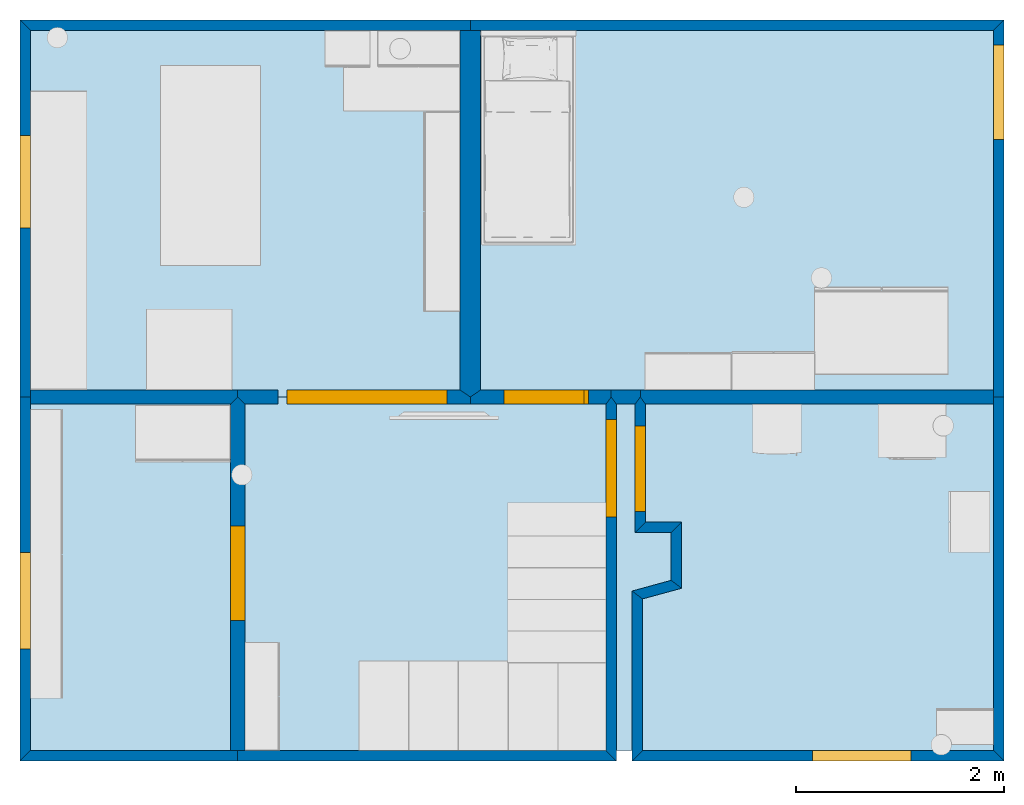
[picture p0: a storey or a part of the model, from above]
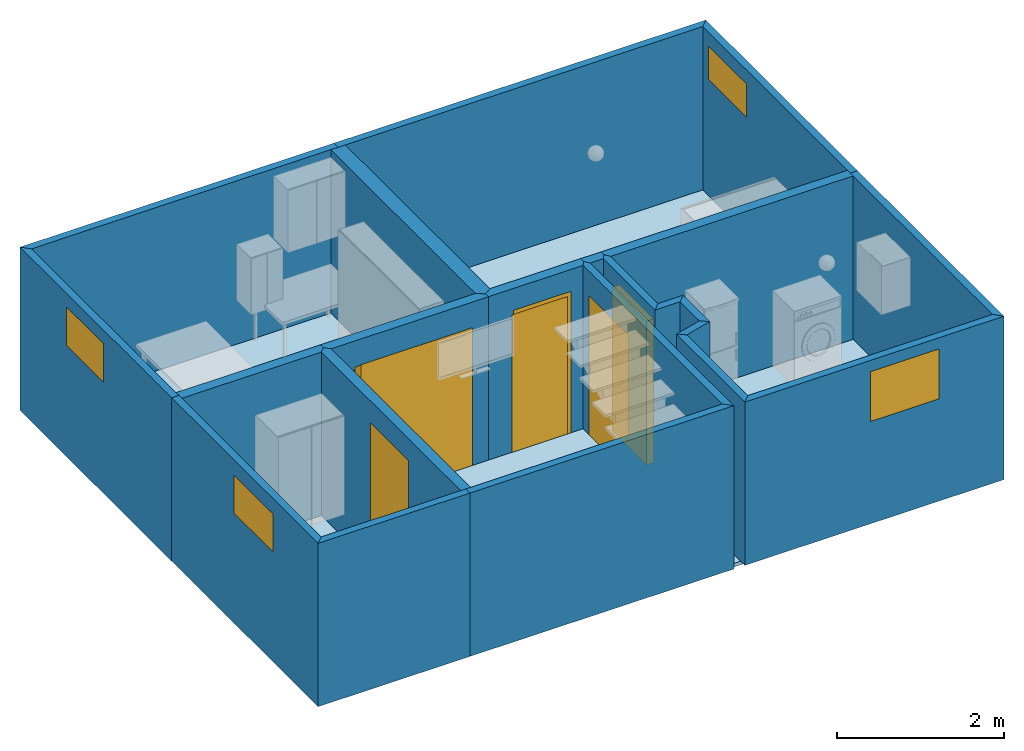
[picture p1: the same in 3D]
Properties of the parts of a building model (IFC2X3)

# File
Description: ViewDefinition [CoordinationView]
Time: 2025-05-22T09:41:32
Author: Metaroom
Written by: IfcOpenShell v0.7.0-f7c03db75
Made in: INDUSTRY_FOUNDATION_CLASSES_ARCHICAD

# IfcSite, Site
RefLatitude: 14, 49, 2; RefLongitude: 17, 34, 41
MetaroomProperties - UpVector: (np.float64(0.0), np.float64(0.0), np.float64(1.0)); IsLeftHandedCoordinateSystem: no

# IfcBuilding, Building
Pset_BuildingCommon - NumberOfStoreys: 3

# IfcBuildingStorey (3)
In: Building
Pset_BuildingStoreyCommon - EntranceLevel: no; GrossPlannedArea: 0; NetPlannedArea: 0
Qto_BuildingStoreyBaseQuantities - GrossPerimeter: 0 m; GrossFloorArea: 0 m2; NetFloorArea: 0 m2; GrossVolume: 0; NetVolume: 0
Name | Elevation (m) | GrossHeight (m) = NetHeight (m)
Story 0 | 0.05 | 2.38766
Story 1 | 2.8867 | 2.53528
Story 2 | 5.74363 | 2.50459

# IfcSpace (15)
Type - PredefinedType: USERDEFINED
InteriorOrExteriorSpace: INTERNAL
Name | In
001 | Story 0
002 | Story 0
003 | Story 0
004 | Story 0
005 | Story 0
006 | Story 1
007 | Story 1
008 | Story 1
009 | Story 1
010 | Story 2
011 | Story 2
012 | Story 2
013 | Story 2
014 | Story 2
015 | Story 2

# IfcDoor (15)
Type - ParameterTakesPrecedence: no; Sizeable: no
Type - IfcDoorLiningProperties - LiningDepth: 0.025 m; LiningThickness: 0.1 m
Name | In | OverallHeight (m) | OverallWidth (m)
Door | Story 0 | 2.01129 | 1.54185
Door | Story 0 | 2.06715 | 0.792596
Door | Story 0 | 2.00865 | 0.768483
Door | Story 0 | 2.10208 | 0.823526
Door | Story 0 | 2.06715 | 0.91323
Door | Story 0 | 2.03054 | 0.938533
Door | Story 2 | 2.1692 | 0.96775
Door | Story 2 | 2.18931 | 0.862838
Door | Story 2 | 2.09763 | 0.866465
Door | Story 2 | 2.11875 | 0.834355
Door | Story 2 | 2.14534 | 0.838237
Door | Story 1 | 2.07098 | 0.88822
Door | Story 1 | 2.10671 | 0.830266
Door | Story 1 | 2.04657 | 0.855807
Door | Story 1 | 2.06386 | 0.855014

# IfcFurnishingElement: Bathtub
In: 012
Type - ElementType: Bathtub

# IfcFurnishingElement: Bed (4)
Type - ElementType: Bed
Name | In
Bed | 002
Bed | 010
Bed | 011
Bed | 013

# IfcFurnishingElement: Chair (10)
Type - ElementType: Chair
Name | In
Chair | 010
Chair | 011
Chair | 013
Chair | 015
5 x Chair | 006
Chair | 008

# IfcFurnishingElement: Oven
In: 006
Type - ElementType: Oven

# IfcFurnishingElement: Refrigerator (2)
Type - ElementType: Refrigerator
Name | In
Refrigerator | 003
Refrigerator | 006

# IfcFurnishingElement: STAIRS (4)
Type - ElementType: STAIRS
Name | In
2 x STAIRS | 005
2 x STAIRS | 009

# IfcFurnishingElement: Sink (3)
Type - ElementType: Sink
Name | In
Sink | 012
Sink | 006
Sink | 007

# IfcFurnishingElement: Sofa
In: 006
Type - ElementType: Sofa

# IfcFurnishingElement: Storage (35)
Type - ElementType: Storage
Name | In
3 x Storage | 001
3 x Storage | 002
2 x Storage | 003
2 x Storage | 004
Storage | 005
2 x Storage | 010
Storage | 011
2 x Storage | 012
Storage | 013
Storage | 015
11 x Storage | 006
2 x Storage | 007
Storage | 008
3 x Storage | 009

# IfcFurnishingElement: Stove
In: 006
Type - ElementType: Stove

# IfcFurnishingElement: Table (13)
Type - ElementType: Table
Name | In
4 x Table | 001
Table | 010
Table | 011
2 x Table | 013
2 x Table | 015
2 x Table | 006
Table | 008

# IfcFurnishingElement: Television (2)
Type - ElementType: Television
Name | In
Television | 005
Television | 006

# IfcFurnishingElement: Toilet (2)
Type - ElementType: Toilet
Name | In
Toilet | 012
Toilet | 007

# IfcFurnishingElement: Washerdryer
In: 003
Type - ElementType: Washerdryer

# IfcOpeningElement: OPENING (36)
Qto_OpeningElementBaseQuantities - Volume: 0
Name | In | Width (m) | Height (m) | Perimeter (m) | Area (m2)
OpeningElement | Story 0 | 0.8927 | 0.559984 | 2.90537 | 0.499898
OpeningElement | Story 0 | 2.00219 | 0.809029 | 5.62244 | 1.61983
OpeningElement | Story 0 | 2.01129 | 1.54185 | 7.10627 | 3.1011
OpeningElement | Story 0 | 0.908887 | 0.484344 | 2.78646 | 0.440214
OpeningElement | Story 0 | 2.06715 | 0.792596 | 5.71948 | 1.63841
OpeningElement | Story 0 | 2.00865 | 0.768482 | 5.55426 | 1.54361
OpeningElement | Story 0 | 0.9474 | 0.727654 | 3.35011 | 0.689379
OpeningElement | Story 0 | 2.10208 | 0.823526 | 5.85122 | 1.73112
OpeningElement | Story 0 | 0.929664 | 0.553371 | 2.96607 | 0.514449
OpeningElement | Story 0 | 2.06715 | 0.91323 | 5.96075 | 1.88778
OpeningElement | Story 0 | 2.03054 | 0.938533 | 5.93815 | 1.90573
OpeningElement | Story 2 | 2.1692 | 0.96775 | 6.2739 | 2.09924
OpeningElement | Story 2 | 0.90068 | 1.20246 | 4.20628 | 1.08303
OpeningElement | Story 2 | 0.920661 | 1.28316 | 4.40765 | 1.18136
OpeningElement | Story 2 | 1.72783 | 1.27812 | 6.0119 | 2.20837
OpeningElement | Story 2 | 2.18931 | 0.862838 | 6.10431 | 1.88902
OpeningElement | Story 2 | 0.850925 | 1.22357 | 4.14899 | 1.04117
OpeningElement | Story 2 | 0.866465 | 2.09763 | 5.92819 | 1.81752
OpeningElement | Story 2 | 0.862989 | 1.17872 | 4.08341 | 1.01722
OpeningElement | Story 2 | 0.891024 | 1.23639 | 4.25483 | 1.10166
OpeningElement | Story 2 | 2.11875 | 0.834355 | 5.9062 | 1.76779
OpeningElement | Story 2 | 2.14534 | 0.838237 | 5.96715 | 1.7983
OpeningElement | Story 2 | 0.897375 | 1.11817 | 4.03109 | 1.00342
OpeningElement | Story 2 | 1.71222 | 1.25125 | 5.92694 | 2.14241
OpeningElement | Story 1 | 0.872123 | 1.23398 | 4.21221 | 1.07618
OpeningElement | Story 1 | 2.16554 | 0.856267 | 6.0436 | 1.85428
OpeningElement | Story 1 | 0.933095 | 1.18499 | 4.23617 | 1.10571
OpeningElement | Story 1 | 2.2103 | 0.862471 | 6.14554 | 1.90632
OpeningElement | Story 1 | 2.29491 | 2.58741 | 9.76465 | 5.93788
OpeningElement | Story 1 | 2.18915 | 0.841435 | 6.06117 | 1.84203
OpeningElement | Story 1 | 2.07098 | 0.88822 | 5.91841 | 1.83949
OpeningElement | Story 1 | 2.10671 | 0.830266 | 5.87395 | 1.74913
OpeningElement | Story 1 | 0.532593 | 0.968261 | 3.00171 | 0.515689
OpeningElement | Story 1 | 0.553337 | 0.946868 | 3.00041 | 0.523937
OpeningElement | Story 1 | 2.04657 | 0.855807 | 5.80475 | 1.75147
OpeningElement | Story 1 | 2.06386 | 0.855014 | 5.83774 | 1.76463

# IfcSlab: Floor:Floor-Grnd-Susp_65Scr-80Ins-100Blk-75PC (20)
Type - PredefinedType: FLOOR
Name | In
6 x Floor | Story 0
9 x Floor | Story 2
5 x Floor | Story 1

# IfcWallStandardCase (80)
Type - PredefinedType: STANDARD
Pset_WallCommon - IsExternal: no; ExtendToStructure: yes
Qto_WallBaseQuantities - Width: 0 m; GrossSideArea: 0 m2; NetSideArea: 0 m2; GrossVolume: 0; NetVolume: 0; GrossWeight: 0; NetWeight: 0
Name | In | Length (m) | Height (m) | GrossFootprintArea (m2) | NetFootprintArea (m2)
Wall | Story 0 | 3.53234 | 2.38766 | 8.43404 | 8.43404
Wall | Story 0 | 4.2388 | 2.38766 | 10.1208 | 10.1208
Wall | Story 0 | 3.53234 | 2.38766 | 8.43404 | 7.93414
Wall | Story 0 | 2.38766 | 1.99678 | 4.76764 | 4.76764
Wall | Story 0 | 2.38766 | 2.24202 | 5.35317 | 2.07435
Wall | Story 0 | 3.53234 | 2.38766 | 8.43404 | 7.99382
Wall | Story 0 | 3.40427 | 2.38766 | 8.12825 | 8.12825
Wall | Story 0 | 2.38766 | 0.280206 | 0.669038 | 0.669038
Wall | Story 0 | 5.04155 | 2.38766 | 12.0375 | 12.0375
Wall | Story 0 | 2.38766 | 1.35707 | 3.24022 | 1.55521
Wall | Story 0 | 0.547844 | 2.38766 | 1.30807 | 1.30807
Wall | Story 0 | 0.34766 | 2.38766 | 0.830093 | 0.830093
Wall | Story 0 | 3.40669 | 2.38766 | 8.13401 | 8.13401
Wall | Story 0 | 0.389622 | 2.38766 | 0.930284 | 0.930284
Wall | Story 0 | 3.43239 | 2.38766 | 8.19538 | 7.506
Wall | Story 0 | 1.49937 | 2.38766 | 3.57998 | 3.57998
Wall | Story 0 | 1.25653 | 2.38766 | 3.00018 | 1.26905
Wall | Story 0 | 1.99678 | 2.38766 | 4.76764 | 4.76764
Wall | Story 0 | 3.40668 | 2.38766 | 8.13401 | 7.61956
Wall | Story 0 | 3.40668 | 2.38766 | 8.13401 | 6.24623
Wall | Story 0 | 3.40668 | 2.38766 | 8.13401 | 6.22827
Wall | Story 0 | 3.59909 | 2.38766 | 8.59339 | 8.59339
Wall | Story 2 | 2.50459 | 1.29435 | 3.24181 | 1.14257
Wall | Story 2 | 2.50459 | 0.224419 | 0.562077 | 0.562077
Wall | Story 2 | 2.50459 | 0.856442 | 2.14504 | 2.14504
Wall | Story 2 | 3.57663 | 2.50459 | 8.95799 | 8.95799
Wall | Story 2 | 3.18045 | 2.50459 | 7.96572 | 6.88269
Wall | Story 2 | 2.50459 | 0.805239 | 2.01679 | 2.01679
Wall | Story 2 | 3.57663 | 2.50459 | 8.95799 | 7.77663
Wall | Story 2 | 3.58089 | 2.50459 | 8.96865 | 8.96865
Wall | Story 2 | 0.699252 | 2.50459 | 1.75134 | 1.75134
2 x Wall | Story 2 | 0.522819 | 2.50459 | 1.30945 | 1.30945
Wall | Story 2 | 3.42645 | 2.50459 | 8.58186 | 6.37348
Wall | Story 2 | 2.7601 | 2.50459 | 6.91291 | 6.91291
Wall | Story 2 | 2.50459 | 1.48538 | 3.72026 | 3.72026
Wall | Story 2 | 0.525509 | 2.50459 | 1.31619 | 1.31619
Wall | Story 2 | 1.08941 | 2.50459 | 2.72852 | 0.839492
Wall | Story 2 | 0.224418 | 2.50459 | 0.562075 | 0.562075
Wall | Story 2 | 0.873736 | 2.50459 | 2.18835 | 2.18835
Wall | Story 2 | 0.857504 | 2.50459 | 2.14769 | 2.14769
Wall | Story 2 | 1.31101 | 2.50459 | 3.28355 | 3.28355
Wall | Story 2 | 1.96515 | 2.50459 | 4.92189 | 3.88073
Wall | Story 2 | 2.31346 | 2.50459 | 5.79427 | 5.79427
Wall | Story 2 | 0.865272 | 2.50459 | 2.16715 | 2.16715
Wall | Story 2 | 0.179228 | 2.50459 | 0.448894 | 0.448894
Wall | Story 2 | 3.21762 | 2.50459 | 8.05882 | 8.05882
Wall | Story 2 | 0.268196 | 2.50459 | 0.671722 | 0.671722
Wall | Story 2 | 1.33046 | 2.50459 | 3.33226 | 1.51473
Wall | Story 2 | 1.15951 | 2.50459 | 2.90409 | 2.90409
Wall | Story 2 | 3.59989 | 2.50459 | 9.01626 | 7.99904
Wall | Story 2 | 2.79214 | 2.50459 | 6.99317 | 5.89151
Wall | Story 2 | 1.28967 | 2.50459 | 3.2301 | 1.46232
Wall | Story 2 | 1.87783 | 2.50459 | 4.70318 | 4.70318
Wall | Story 2 | 2.50459 | 1.35088 | 3.38339 | 1.58509
Wall | Story 2 | 2.50459 | 2.41763 | 6.05518 | 5.05176
Wall | Story 2 | 2.50459 | 0.525509 | 1.31618 | 1.31618
Wall | Story 2 | 1.39422 | 2.50459 | 3.49196 | 3.49196
Wall | Story 2 | 2.50459 | 0.262521 | 0.657507 | 0.657507
Wall | Story 2 | 3.24249 | 2.50459 | 8.12111 | 5.97869
Wall | Story 1 | 0.28812 | 2.53528 | 0.730467 | 0.730467
Wall | Story 1 | 7.10385 | 2.53528 | 18.0103 | 15.0798
Wall | Story 1 | 2.53528 | 1.8525 | 4.69662 | 4.69662
Wall | Story 1 | 3.3 | 2.53528 | 8.36643 | 8.36643
Wall | Story 1 | 0.537354 | 2.53528 | 1.36235 | 1.36235
Wall | Story 1 | 1.55088 | 2.53528 | 3.93192 | 3.93192
Wall | Story 1 | 0.582061 | 2.53528 | 1.47569 | 1.47569
Wall | Story 1 | 1.49098 | 2.53528 | 3.78006 | 3.78006
Wall | Story 1 | 3.47993 | 2.53528 | 8.8226 | 7.71689
Wall | Story 1 | 9.42408 | 2.53528 | 23.8927 | 14.2065
Wall | Story 1 | 3.84434 | 2.53528 | 9.7465 | 7.90701
Wall | Story 1 | 2.53528 | 0.178001 | 0.451284 | 0.451284
Wall | Story 1 | 1.81915 | 2.53528 | 4.61205 | 2.86292
Wall | Story 1 | 1.8525 | 2.53528 | 4.69663 | 4.69663
Wall | Story 1 | 1.81915 | 2.53528 | 4.61205 | 4.09637
Wall | Story 1 | 1.8525 | 2.53528 | 4.69662 | 4.69662
Wall | Story 1 | 1.54263 | 2.53528 | 3.911 | 3.38706
Wall | Story 1 | 2.53528 | 1.54197 | 3.90932 | 2.15786
Wall | Story 1 | 2.53528 | 1.81024 | 4.58946 | 4.58946
Wall | Story 1 | 3.84434 | 2.53528 | 9.74649 | 7.98187

# IfcWindow (20)
Type - ConstructionType: ALUMINIUM; OperationType: SINGLE_PANEL; ParameterTakesPrecedence: yes; Sizeable: yes
Type - IfcWindowLiningProperties - LiningDepth: 0.025 m; LiningThickness: 0.1 m
OverallHeight: 1.5 m; OverallWidth: 0.5 m
Name | In
4 x Window | Story 0
8 x Window | Story 2
8 x Window | Story 1
